VERSION 5.8 ;
BUSBITCHARS "[]" ;
DIVIDERCHAR "/" ;
UNITS
    DATABASE MICRONS 1000 ;
END UNITS

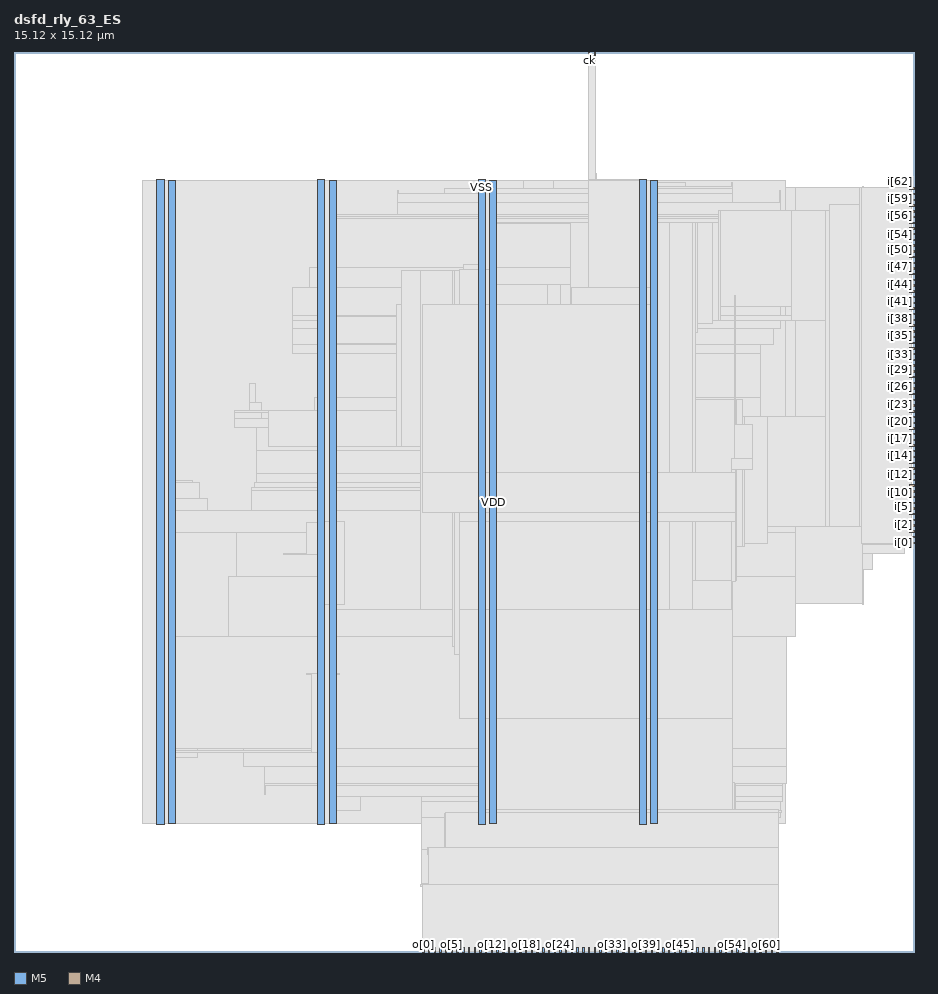
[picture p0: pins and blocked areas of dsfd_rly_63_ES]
MACRO dsfd_rly_63_ES
  FOREIGN dsfd_rly_63_ES 0 0 ;
  CLASS BLOCK ;
  SIZE 15.12 BY 15.12 ;
  PIN ck
    DIRECTION INPUT ;
    USE SIGNAL ;
    PORT
      LAYER M5 ;
        RECT  9.648 15.036 9.672 15.12 ;
    END
  END ck
  PIN i[0]
    DIRECTION INPUT ;
    USE SIGNAL ;
    PORT
      LAYER M4 ;
        RECT  15.036 6.864 15.12 6.888 ;
    END
  END i[0]
  PIN i[10]
    DIRECTION INPUT ;
    USE SIGNAL ;
    PORT
      LAYER M4 ;
        RECT  15.036 7.824 15.12 7.848 ;
    END
  END i[10]
  PIN i[11]
    DIRECTION INPUT ;
    USE SIGNAL ;
    PORT
      LAYER M4 ;
        RECT  15.036 7.92 15.12 7.944 ;
    END
  END i[11]
  PIN i[12]
    DIRECTION INPUT ;
    USE SIGNAL ;
    PORT
      LAYER M4 ;
        RECT  15.036 8.016 15.12 8.04 ;
    END
  END i[12]
  PIN i[13]
    DIRECTION INPUT ;
    USE SIGNAL ;
    PORT
      LAYER M4 ;
        RECT  15.036 8.112 15.12 8.136 ;
    END
  END i[13]
  PIN i[14]
    DIRECTION INPUT ;
    USE SIGNAL ;
    PORT
      LAYER M4 ;
        RECT  15.036 8.208 15.12 8.232 ;
    END
  END i[14]
  PIN i[15]
    DIRECTION INPUT ;
    USE SIGNAL ;
    PORT
      LAYER M4 ;
        RECT  15.036 8.304 15.12 8.328 ;
    END
  END i[15]
  PIN i[16]
    DIRECTION INPUT ;
    USE SIGNAL ;
    PORT
      LAYER M4 ;
        RECT  15.036 8.4 15.12 8.424 ;
    END
  END i[16]
  PIN i[17]
    DIRECTION INPUT ;
    USE SIGNAL ;
    PORT
      LAYER M4 ;
        RECT  15.036 8.496 15.12 8.52 ;
    END
  END i[17]
  PIN i[18]
    DIRECTION INPUT ;
    USE SIGNAL ;
    PORT
      LAYER M4 ;
        RECT  15.036 8.592 15.12 8.616 ;
    END
  END i[18]
  PIN i[19]
    DIRECTION INPUT ;
    USE SIGNAL ;
    PORT
      LAYER M4 ;
        RECT  15.036 8.688 15.12 8.712 ;
    END
  END i[19]
  PIN i[1]
    DIRECTION INPUT ;
    USE SIGNAL ;
    PORT
      LAYER M4 ;
        RECT  15.036 6.96 15.12 6.984 ;
    END
  END i[1]
  PIN i[20]
    DIRECTION INPUT ;
    USE SIGNAL ;
    PORT
      LAYER M4 ;
        RECT  15.036 8.784 15.12 8.808 ;
    END
  END i[20]
  PIN i[21]
    DIRECTION INPUT ;
    USE SIGNAL ;
    PORT
      LAYER M4 ;
        RECT  15.036 8.88 15.12 8.904 ;
    END
  END i[21]
  PIN i[22]
    DIRECTION INPUT ;
    USE SIGNAL ;
    PORT
      LAYER M4 ;
        RECT  15.036 8.976 15.12 9 ;
    END
  END i[22]
  PIN i[23]
    DIRECTION INPUT ;
    USE SIGNAL ;
    PORT
      LAYER M4 ;
        RECT  15.036 9.072 15.12 9.096 ;
    END
  END i[23]
  PIN i[24]
    DIRECTION INPUT ;
    USE SIGNAL ;
    PORT
      LAYER M4 ;
        RECT  15.036 9.168 15.12 9.192 ;
    END
  END i[24]
  PIN i[25]
    DIRECTION INPUT ;
    USE SIGNAL ;
    PORT
      LAYER M4 ;
        RECT  15.036 9.264 15.12 9.288 ;
    END
  END i[25]
  PIN i[26]
    DIRECTION INPUT ;
    USE SIGNAL ;
    PORT
      LAYER M4 ;
        RECT  15.036 9.36 15.12 9.384 ;
    END
  END i[26]
  PIN i[27]
    DIRECTION INPUT ;
    USE SIGNAL ;
    PORT
      LAYER M4 ;
        RECT  15.036 9.456 15.12 9.48 ;
    END
  END i[27]
  PIN i[28]
    DIRECTION INPUT ;
    USE SIGNAL ;
    PORT
      LAYER M4 ;
        RECT  15.036 9.552 15.12 9.576 ;
    END
  END i[28]
  PIN i[29]
    DIRECTION INPUT ;
    USE SIGNAL ;
    PORT
      LAYER M4 ;
        RECT  15.036 9.648 15.12 9.672 ;
    END
  END i[29]
  PIN i[2]
    DIRECTION INPUT ;
    USE SIGNAL ;
    PORT
      LAYER M4 ;
        RECT  15.036 7.056 15.12 7.08 ;
    END
  END i[2]
  PIN i[30]
    DIRECTION INPUT ;
    USE SIGNAL ;
    PORT
      LAYER M4 ;
        RECT  15.036 9.744 15.12 9.768 ;
    END
  END i[30]
  PIN i[31]
    DIRECTION INPUT ;
    USE SIGNAL ;
    PORT
      LAYER M4 ;
        RECT  15.036 9.84 15.12 9.864 ;
    END
  END i[31]
  PIN i[32]
    DIRECTION INPUT ;
    USE SIGNAL ;
    PORT
      LAYER M4 ;
        RECT  15.036 9.936 15.12 9.96 ;
    END
  END i[32]
  PIN i[33]
    DIRECTION INPUT ;
    USE SIGNAL ;
    PORT
      LAYER M4 ;
        RECT  15.036 10.032 15.12 10.056 ;
    END
  END i[33]
  PIN i[34]
    DIRECTION INPUT ;
    USE SIGNAL ;
    PORT
      LAYER M4 ;
        RECT  15.036 10.128 15.12 10.152 ;
    END
  END i[34]
  PIN i[35]
    DIRECTION INPUT ;
    USE SIGNAL ;
    PORT
      LAYER M4 ;
        RECT  15.036 10.224 15.12 10.248 ;
    END
  END i[35]
  PIN i[36]
    DIRECTION INPUT ;
    USE SIGNAL ;
    PORT
      LAYER M4 ;
        RECT  15.036 10.32 15.12 10.344 ;
    END
  END i[36]
  PIN i[37]
    DIRECTION INPUT ;
    USE SIGNAL ;
    PORT
      LAYER M4 ;
        RECT  15.036 10.416 15.12 10.44 ;
    END
  END i[37]
  PIN i[38]
    DIRECTION INPUT ;
    USE SIGNAL ;
    PORT
      LAYER M4 ;
        RECT  15.036 10.512 15.12 10.536 ;
    END
  END i[38]
  PIN i[39]
    DIRECTION INPUT ;
    USE SIGNAL ;
    PORT
      LAYER M4 ;
        RECT  15.036 10.608 15.12 10.632 ;
    END
  END i[39]
  PIN i[3]
    DIRECTION INPUT ;
    USE SIGNAL ;
    PORT
      LAYER M4 ;
        RECT  15.036 7.152 15.12 7.176 ;
    END
  END i[3]
  PIN i[40]
    DIRECTION INPUT ;
    USE SIGNAL ;
    PORT
      LAYER M4 ;
        RECT  15.036 10.704 15.12 10.728 ;
    END
  END i[40]
  PIN i[41]
    DIRECTION INPUT ;
    USE SIGNAL ;
    PORT
      LAYER M4 ;
        RECT  15.036 10.8 15.12 10.824 ;
    END
  END i[41]
  PIN i[42]
    DIRECTION INPUT ;
    USE SIGNAL ;
    PORT
      LAYER M4 ;
        RECT  15.036 10.896 15.12 10.92 ;
    END
  END i[42]
  PIN i[43]
    DIRECTION INPUT ;
    USE SIGNAL ;
    PORT
      LAYER M4 ;
        RECT  15.036 10.992 15.12 11.016 ;
    END
  END i[43]
  PIN i[44]
    DIRECTION INPUT ;
    USE SIGNAL ;
    PORT
      LAYER M4 ;
        RECT  15.036 11.088 15.12 11.112 ;
    END
  END i[44]
  PIN i[45]
    DIRECTION INPUT ;
    USE SIGNAL ;
    PORT
      LAYER M4 ;
        RECT  15.036 11.184 15.12 11.208 ;
    END
  END i[45]
  PIN i[46]
    DIRECTION INPUT ;
    USE SIGNAL ;
    PORT
      LAYER M4 ;
        RECT  15.036 11.28 15.12 11.304 ;
    END
  END i[46]
  PIN i[47]
    DIRECTION INPUT ;
    USE SIGNAL ;
    PORT
      LAYER M4 ;
        RECT  15.036 11.376 15.12 11.4 ;
    END
  END i[47]
  PIN i[48]
    DIRECTION INPUT ;
    USE SIGNAL ;
    PORT
      LAYER M4 ;
        RECT  15.036 11.472 15.12 11.496 ;
    END
  END i[48]
  PIN i[49]
    DIRECTION INPUT ;
    USE SIGNAL ;
    PORT
      LAYER M4 ;
        RECT  15.036 11.568 15.12 11.592 ;
    END
  END i[49]
  PIN i[4]
    DIRECTION INPUT ;
    USE SIGNAL ;
    PORT
      LAYER M4 ;
        RECT  15.036 7.248 15.12 7.272 ;
    END
  END i[4]
  PIN i[50]
    DIRECTION INPUT ;
    USE SIGNAL ;
    PORT
      LAYER M4 ;
        RECT  15.036 11.664 15.12 11.688 ;
    END
  END i[50]
  PIN i[51]
    DIRECTION INPUT ;
    USE SIGNAL ;
    PORT
      LAYER M4 ;
        RECT  15.036 11.76 15.12 11.784 ;
    END
  END i[51]
  PIN i[52]
    DIRECTION INPUT ;
    USE SIGNAL ;
    PORT
      LAYER M4 ;
        RECT  15.036 11.856 15.12 11.88 ;
    END
  END i[52]
  PIN i[53]
    DIRECTION INPUT ;
    USE SIGNAL ;
    PORT
      LAYER M4 ;
        RECT  15.036 11.952 15.12 11.976 ;
    END
  END i[53]
  PIN i[54]
    DIRECTION INPUT ;
    USE SIGNAL ;
    PORT
      LAYER M4 ;
        RECT  15.036 12.048 15.12 12.072 ;
    END
  END i[54]
  PIN i[55]
    DIRECTION INPUT ;
    USE SIGNAL ;
    PORT
      LAYER M4 ;
        RECT  15.036 12.144 15.12 12.168 ;
    END
  END i[55]
  PIN i[56]
    DIRECTION INPUT ;
    USE SIGNAL ;
    PORT
      LAYER M4 ;
        RECT  15.036 12.24 15.12 12.264 ;
    END
  END i[56]
  PIN i[57]
    DIRECTION INPUT ;
    USE SIGNAL ;
    PORT
      LAYER M4 ;
        RECT  15.036 12.336 15.12 12.36 ;
    END
  END i[57]
  PIN i[58]
    DIRECTION INPUT ;
    USE SIGNAL ;
    PORT
      LAYER M4 ;
        RECT  15.036 12.432 15.12 12.456 ;
    END
  END i[58]
  PIN i[59]
    DIRECTION INPUT ;
    USE SIGNAL ;
    PORT
      LAYER M4 ;
        RECT  15.036 12.528 15.12 12.552 ;
    END
  END i[59]
  PIN i[5]
    DIRECTION INPUT ;
    USE SIGNAL ;
    PORT
      LAYER M4 ;
        RECT  15.036 7.344 15.12 7.368 ;
    END
  END i[5]
  PIN i[60]
    DIRECTION INPUT ;
    USE SIGNAL ;
    PORT
      LAYER M4 ;
        RECT  15.036 12.624 15.12 12.648 ;
    END
  END i[60]
  PIN i[61]
    DIRECTION INPUT ;
    USE SIGNAL ;
    PORT
      LAYER M4 ;
        RECT  15.036 12.72 15.12 12.744 ;
    END
  END i[61]
  PIN i[62]
    DIRECTION INPUT ;
    USE SIGNAL ;
    PORT
      LAYER M4 ;
        RECT  15.036 12.816 15.12 12.84 ;
    END
  END i[62]
  PIN i[6]
    DIRECTION INPUT ;
    USE SIGNAL ;
    PORT
      LAYER M4 ;
        RECT  15.036 7.44 15.12 7.464 ;
    END
  END i[6]
  PIN i[7]
    DIRECTION INPUT ;
    USE SIGNAL ;
    PORT
      LAYER M4 ;
        RECT  15.036 7.536 15.12 7.56 ;
    END
  END i[7]
  PIN i[8]
    DIRECTION INPUT ;
    USE SIGNAL ;
    PORT
      LAYER M4 ;
        RECT  15.036 7.632 15.12 7.656 ;
    END
  END i[8]
  PIN i[9]
    DIRECTION INPUT ;
    USE SIGNAL ;
    PORT
      LAYER M4 ;
        RECT  15.036 7.728 15.12 7.752 ;
    END
  END i[9]
  PIN o[0]
    DIRECTION OUTPUT ;
    USE SIGNAL ;
    PORT
      LAYER M5 ;
        RECT  6.864 0 6.888 0.084 ;
    END
  END o[0]
  PIN o[10]
    DIRECTION OUTPUT ;
    USE SIGNAL ;
    PORT
      LAYER M5 ;
        RECT  7.824 0 7.848 0.084 ;
    END
  END o[10]
  PIN o[11]
    DIRECTION OUTPUT ;
    USE SIGNAL ;
    PORT
      LAYER M5 ;
        RECT  7.92 0 7.944 0.084 ;
    END
  END o[11]
  PIN o[12]
    DIRECTION OUTPUT ;
    USE SIGNAL ;
    PORT
      LAYER M5 ;
        RECT  8.016 0 8.04 0.084 ;
    END
  END o[12]
  PIN o[13]
    DIRECTION OUTPUT ;
    USE SIGNAL ;
    PORT
      LAYER M5 ;
        RECT  8.112 0 8.136 0.084 ;
    END
  END o[13]
  PIN o[14]
    DIRECTION OUTPUT ;
    USE SIGNAL ;
    PORT
      LAYER M5 ;
        RECT  8.208 0 8.232 0.084 ;
    END
  END o[14]
  PIN o[15]
    DIRECTION OUTPUT ;
    USE SIGNAL ;
    PORT
      LAYER M5 ;
        RECT  8.304 0 8.328 0.084 ;
    END
  END o[15]
  PIN o[16]
    DIRECTION OUTPUT ;
    USE SIGNAL ;
    PORT
      LAYER M5 ;
        RECT  8.4 0 8.424 0.084 ;
    END
  END o[16]
  PIN o[17]
    DIRECTION OUTPUT ;
    USE SIGNAL ;
    PORT
      LAYER M5 ;
        RECT  8.496 0 8.52 0.084 ;
    END
  END o[17]
  PIN o[18]
    DIRECTION OUTPUT ;
    USE SIGNAL ;
    PORT
      LAYER M5 ;
        RECT  8.592 0 8.616 0.084 ;
    END
  END o[18]
  PIN o[19]
    DIRECTION OUTPUT ;
    USE SIGNAL ;
    PORT
      LAYER M5 ;
        RECT  8.688 0 8.712 0.084 ;
    END
  END o[19]
  PIN o[1]
    DIRECTION OUTPUT ;
    USE SIGNAL ;
    PORT
      LAYER M5 ;
        RECT  6.96 0 6.984 0.084 ;
    END
  END o[1]
  PIN o[20]
    DIRECTION OUTPUT ;
    USE SIGNAL ;
    PORT
      LAYER M5 ;
        RECT  8.784 0 8.808 0.084 ;
    END
  END o[20]
  PIN o[21]
    DIRECTION OUTPUT ;
    USE SIGNAL ;
    PORT
      LAYER M5 ;
        RECT  8.88 0 8.904 0.084 ;
    END
  END o[21]
  PIN o[22]
    DIRECTION OUTPUT ;
    USE SIGNAL ;
    PORT
      LAYER M5 ;
        RECT  8.976 0 9 0.084 ;
    END
  END o[22]
  PIN o[23]
    DIRECTION OUTPUT ;
    USE SIGNAL ;
    PORT
      LAYER M5 ;
        RECT  9.072 0 9.096 0.084 ;
    END
  END o[23]
  PIN o[24]
    DIRECTION OUTPUT ;
    USE SIGNAL ;
    PORT
      LAYER M5 ;
        RECT  9.168 0 9.192 0.084 ;
    END
  END o[24]
  PIN o[25]
    DIRECTION OUTPUT ;
    USE SIGNAL ;
    PORT
      LAYER M5 ;
        RECT  9.264 0 9.288 0.084 ;
    END
  END o[25]
  PIN o[26]
    DIRECTION OUTPUT ;
    USE SIGNAL ;
    PORT
      LAYER M5 ;
        RECT  9.36 0 9.384 0.084 ;
    END
  END o[26]
  PIN o[27]
    DIRECTION OUTPUT ;
    USE SIGNAL ;
    PORT
      LAYER M5 ;
        RECT  9.456 0 9.48 0.084 ;
    END
  END o[27]
  PIN o[28]
    DIRECTION OUTPUT ;
    USE SIGNAL ;
    PORT
      LAYER M5 ;
        RECT  9.552 0 9.576 0.084 ;
    END
  END o[28]
  PIN o[29]
    DIRECTION OUTPUT ;
    USE SIGNAL ;
    PORT
      LAYER M5 ;
        RECT  9.648 0 9.672 0.084 ;
    END
  END o[29]
  PIN o[2]
    DIRECTION OUTPUT ;
    USE SIGNAL ;
    PORT
      LAYER M5 ;
        RECT  7.056 0 7.08 0.084 ;
    END
  END o[2]
  PIN o[30]
    DIRECTION OUTPUT ;
    USE SIGNAL ;
    PORT
      LAYER M5 ;
        RECT  9.744 0 9.768 0.084 ;
    END
  END o[30]
  PIN o[31]
    DIRECTION OUTPUT ;
    USE SIGNAL ;
    PORT
      LAYER M5 ;
        RECT  9.84 0 9.864 0.084 ;
    END
  END o[31]
  PIN o[32]
    DIRECTION OUTPUT ;
    USE SIGNAL ;
    PORT
      LAYER M5 ;
        RECT  9.936 0 9.96 0.084 ;
    END
  END o[32]
  PIN o[33]
    DIRECTION OUTPUT ;
    USE SIGNAL ;
    PORT
      LAYER M5 ;
        RECT  10.032 0 10.056 0.084 ;
    END
  END o[33]
  PIN o[34]
    DIRECTION OUTPUT ;
    USE SIGNAL ;
    PORT
      LAYER M5 ;
        RECT  10.128 0 10.152 0.084 ;
    END
  END o[34]
  PIN o[35]
    DIRECTION OUTPUT ;
    USE SIGNAL ;
    PORT
      LAYER M5 ;
        RECT  10.224 0 10.248 0.084 ;
    END
  END o[35]
  PIN o[36]
    DIRECTION OUTPUT ;
    USE SIGNAL ;
    PORT
      LAYER M5 ;
        RECT  10.32 0 10.344 0.084 ;
    END
  END o[36]
  PIN o[37]
    DIRECTION OUTPUT ;
    USE SIGNAL ;
    PORT
      LAYER M5 ;
        RECT  10.416 0 10.44 0.084 ;
    END
  END o[37]
  PIN o[38]
    DIRECTION OUTPUT ;
    USE SIGNAL ;
    PORT
      LAYER M5 ;
        RECT  10.512 0 10.536 0.084 ;
    END
  END o[38]
  PIN o[39]
    DIRECTION OUTPUT ;
    USE SIGNAL ;
    PORT
      LAYER M5 ;
        RECT  10.608 0 10.632 0.084 ;
    END
  END o[39]
  PIN o[3]
    DIRECTION OUTPUT ;
    USE SIGNAL ;
    PORT
      LAYER M5 ;
        RECT  7.152 0 7.176 0.084 ;
    END
  END o[3]
  PIN o[40]
    DIRECTION OUTPUT ;
    USE SIGNAL ;
    PORT
      LAYER M5 ;
        RECT  10.704 0 10.728 0.084 ;
    END
  END o[40]
  PIN o[41]
    DIRECTION OUTPUT ;
    USE SIGNAL ;
    PORT
      LAYER M5 ;
        RECT  10.8 0 10.824 0.084 ;
    END
  END o[41]
  PIN o[42]
    DIRECTION OUTPUT ;
    USE SIGNAL ;
    PORT
      LAYER M5 ;
        RECT  10.896 0 10.92 0.084 ;
    END
  END o[42]
  PIN o[43]
    DIRECTION OUTPUT ;
    USE SIGNAL ;
    PORT
      LAYER M5 ;
        RECT  10.992 0 11.016 0.084 ;
    END
  END o[43]
  PIN o[44]
    DIRECTION OUTPUT ;
    USE SIGNAL ;
    PORT
      LAYER M5 ;
        RECT  11.088 0 11.112 0.084 ;
    END
  END o[44]
  PIN o[45]
    DIRECTION OUTPUT ;
    USE SIGNAL ;
    PORT
      LAYER M5 ;
        RECT  11.184 0 11.208 0.084 ;
    END
  END o[45]
  PIN o[46]
    DIRECTION OUTPUT ;
    USE SIGNAL ;
    PORT
      LAYER M5 ;
        RECT  11.28 0 11.304 0.084 ;
    END
  END o[46]
  PIN o[47]
    DIRECTION OUTPUT ;
    USE SIGNAL ;
    PORT
      LAYER M5 ;
        RECT  11.376 0 11.4 0.084 ;
    END
  END o[47]
  PIN o[48]
    DIRECTION OUTPUT ;
    USE SIGNAL ;
    PORT
      LAYER M5 ;
        RECT  11.472 0 11.496 0.084 ;
    END
  END o[48]
  PIN o[49]
    DIRECTION OUTPUT ;
    USE SIGNAL ;
    PORT
      LAYER M5 ;
        RECT  11.568 0 11.592 0.084 ;
    END
  END o[49]
  PIN o[4]
    DIRECTION OUTPUT ;
    USE SIGNAL ;
    PORT
      LAYER M5 ;
        RECT  7.248 0 7.272 0.084 ;
    END
  END o[4]
  PIN o[50]
    DIRECTION OUTPUT ;
    USE SIGNAL ;
    PORT
      LAYER M5 ;
        RECT  11.664 0 11.688 0.084 ;
    END
  END o[50]
  PIN o[51]
    DIRECTION OUTPUT ;
    USE SIGNAL ;
    PORT
      LAYER M5 ;
        RECT  11.76 0 11.784 0.084 ;
    END
  END o[51]
  PIN o[52]
    DIRECTION OUTPUT ;
    USE SIGNAL ;
    PORT
      LAYER M5 ;
        RECT  11.856 0 11.88 0.084 ;
    END
  END o[52]
  PIN o[53]
    DIRECTION OUTPUT ;
    USE SIGNAL ;
    PORT
      LAYER M5 ;
        RECT  11.952 0 11.976 0.084 ;
    END
  END o[53]
  PIN o[54]
    DIRECTION OUTPUT ;
    USE SIGNAL ;
    PORT
      LAYER M5 ;
        RECT  12.048 0 12.072 0.084 ;
    END
  END o[54]
  PIN o[55]
    DIRECTION OUTPUT ;
    USE SIGNAL ;
    PORT
      LAYER M5 ;
        RECT  12.144 0 12.168 0.084 ;
    END
  END o[55]
  PIN o[56]
    DIRECTION OUTPUT ;
    USE SIGNAL ;
    PORT
      LAYER M5 ;
        RECT  12.24 0 12.264 0.084 ;
    END
  END o[56]
  PIN o[57]
    DIRECTION OUTPUT ;
    USE SIGNAL ;
    PORT
      LAYER M5 ;
        RECT  12.336 0 12.36 0.084 ;
    END
  END o[57]
  PIN o[58]
    DIRECTION OUTPUT ;
    USE SIGNAL ;
    PORT
      LAYER M5 ;
        RECT  12.432 0 12.456 0.084 ;
    END
  END o[58]
  PIN o[59]
    DIRECTION OUTPUT ;
    USE SIGNAL ;
    PORT
      LAYER M5 ;
        RECT  12.528 0 12.552 0.084 ;
    END
  END o[59]
  PIN o[5]
    DIRECTION OUTPUT ;
    USE SIGNAL ;
    PORT
      LAYER M5 ;
        RECT  7.344 0 7.368 0.084 ;
    END
  END o[5]
  PIN o[60]
    DIRECTION OUTPUT ;
    USE SIGNAL ;
    PORT
      LAYER M5 ;
        RECT  12.624 0 12.648 0.084 ;
    END
  END o[60]
  PIN o[61]
    DIRECTION OUTPUT ;
    USE SIGNAL ;
    PORT
      LAYER M5 ;
        RECT  12.72 0 12.744 0.084 ;
    END
  END o[61]
  PIN o[62]
    DIRECTION OUTPUT ;
    USE SIGNAL ;
    PORT
      LAYER M5 ;
        RECT  12.816 0 12.84 0.084 ;
    END
  END o[62]
  PIN o[6]
    DIRECTION OUTPUT ;
    USE SIGNAL ;
    PORT
      LAYER M5 ;
        RECT  7.44 0 7.464 0.084 ;
    END
  END o[6]
  PIN o[7]
    DIRECTION OUTPUT ;
    USE SIGNAL ;
    PORT
      LAYER M5 ;
        RECT  7.536 0 7.56 0.084 ;
    END
  END o[7]
  PIN o[8]
    DIRECTION OUTPUT ;
    USE SIGNAL ;
    PORT
      LAYER M5 ;
        RECT  7.632 0 7.656 0.084 ;
    END
  END o[8]
  PIN o[9]
    DIRECTION OUTPUT ;
    USE SIGNAL ;
    PORT
      LAYER M5 ;
        RECT  7.728 0 7.752 0.084 ;
    END
  END o[9]
  PIN rs
    DIRECTION INPUT ;
    USE SIGNAL ;
    PORT
      LAYER M5 ;
        RECT  9.744 15.036 9.768 15.12 ;
    END
  END rs
  PIN VDD
    DIRECTION INOUT ;
    USE POWER ;
    PORT
      LAYER M5 ;
        RECT  10.692 2.151 10.812 12.969 ;
        RECT  7.992 2.151 8.112 12.969 ;
        RECT  5.292 2.151 5.412 12.969 ;
        RECT  2.592 2.151 2.712 12.969 ;
    END
  END VDD
  PIN VSS
    DIRECTION INOUT ;
    USE GROUND ;
    PORT
      LAYER M5 ;
        RECT  10.5 2.137 10.62 12.983 ;
        RECT  7.8 2.137 7.92 12.983 ;
        RECT  5.1 2.137 5.22 12.983 ;
        RECT  2.4 2.137 2.52 12.983 ;
    END
  END VSS
  OBS
    LAYER RVTN ;
     RECT  2.16 2.16 12.96 2.295 ;
     RECT  2.16 2.565 12.96 2.835 ;
     RECT  2.16 3.105 12.96 3.375 ;
     RECT  2.16 3.645 12.96 3.915 ;
     RECT  2.16 4.185 12.96 4.455 ;
     RECT  2.16 4.725 12.96 4.995 ;
     RECT  2.16 5.265 12.96 5.535 ;
     RECT  2.16 5.805 12.96 6.075 ;
     RECT  2.16 6.345 12.96 6.615 ;
     RECT  2.16 6.885 12.96 7.155 ;
     RECT  2.16 7.425 12.96 7.695 ;
     RECT  2.16 7.965 12.96 8.235 ;
     RECT  2.16 8.505 12.96 8.775 ;
     RECT  2.16 9.045 12.96 9.315 ;
     RECT  2.16 9.585 12.96 9.855 ;
     RECT  2.16 10.125 12.96 10.395 ;
     RECT  2.16 10.665 12.96 10.935 ;
     RECT  2.16 11.205 12.96 11.475 ;
     RECT  2.16 11.745 12.96 12.015 ;
     RECT  2.16 12.285 12.96 12.555 ;
     RECT  2.16 12.825 12.96 12.96 ;
    LAYER RVTP ;
     RECT  2.16 2.295 12.96 2.565 ;
     RECT  2.16 2.835 12.96 3.105 ;
     RECT  2.16 3.375 12.96 3.645 ;
     RECT  2.16 3.915 12.96 4.185 ;
     RECT  2.16 4.455 12.96 4.725 ;
     RECT  2.16 4.995 12.96 5.265 ;
     RECT  2.16 5.535 12.96 5.805 ;
     RECT  2.16 6.075 12.96 6.345 ;
     RECT  2.16 6.615 12.96 6.885 ;
     RECT  2.16 7.155 12.96 7.425 ;
     RECT  2.16 7.695 12.96 7.965 ;
     RECT  2.16 8.235 12.96 8.505 ;
     RECT  2.16 8.775 12.96 9.045 ;
     RECT  2.16 9.315 12.96 9.585 ;
     RECT  2.16 9.855 12.96 10.125 ;
     RECT  2.16 10.395 12.96 10.665 ;
     RECT  2.16 10.935 12.96 11.205 ;
     RECT  2.16 11.475 12.96 11.745 ;
     RECT  2.16 12.015 12.96 12.285 ;
     RECT  2.16 12.555 12.96 12.825 ;
    LAYER M1 ;
     RECT  2.16 2.151 12.96 12.969 ;
    LAYER M2 ;
     RECT  2.16 2.151 8.563 12.969 ;
     RECT  8.563 2.106 9.059 12.969 ;
     RECT  9.059 2.151 12.96 12.969 ;
     RECT  12.96 2.844 12.983 2.862 ;
     RECT  12.96 5.31 13.127 12.852 ;
     RECT  13.127 5.85 14.279 12.852 ;
     RECT  14.279 6.426 14.315 12.546 ;
     RECT  14.315 6.426 14.351 8.874 ;
     RECT  14.315 9.63 14.351 12.348 ;
     RECT  14.351 9.63 14.387 9.918 ;
     RECT  14.351 6.426 14.423 8.838 ;
     RECT  14.423 6.696 14.459 8.838 ;
     RECT  14.459 6.696 14.963 6.876 ;
     RECT  14.387 9.864 14.963 9.918 ;
     RECT  14.459 8.046 14.999 8.064 ;
     RECT  14.963 9.864 14.999 9.882 ;
     RECT  14.351 10.98 14.999 12.348 ;
     RECT  14.963 6.858 15.035 6.876 ;
     RECT  14.459 8.82 15.035 8.838 ;
     RECT  14.999 10.98 15.035 10.998 ;
     RECT  14.999 12.33 15.035 12.348 ;
    LAYER M3 ;
     RECT  8.82 0.091 8.838 0.139 ;
     RECT  12.168 0.091 12.654 0.187 ;
     RECT  7.668 0.091 7.686 0.523 ;
     RECT  7.128 0.523 7.686 1.099 ;
     RECT  6.84 1.099 7.686 1.147 ;
     RECT  8.82 0.139 8.91 1.147 ;
     RECT  12.132 0.187 12.654 1.675 ;
     RECT  6.84 1.147 8.91 1.723 ;
     RECT  10.656 0.091 11.106 1.723 ;
     RECT  12.06 1.675 12.654 1.723 ;
     RECT  6.84 1.723 12.654 2.263 ;
     RECT  5.115 2.143 5.205 2.371 ;
     RECT  2.415 2.143 2.505 2.413 ;
     RECT  6.84 2.263 12.87 2.533 ;
     RECT  5.115 2.371 5.814 2.605 ;
     RECT  6.84 2.533 12.906 2.605 ;
     RECT  4.212 2.641 4.23 2.803 ;
     RECT  5.115 2.605 12.906 2.803 ;
     RECT  4.212 2.803 12.906 2.839 ;
     RECT  4.212 2.839 12.978 3.109 ;
     RECT  2.415 2.413 2.697 3.271 ;
     RECT  2.415 3.271 3.078 3.415 ;
     RECT  3.852 3.109 12.978 3.415 ;
     RECT  2.415 3.415 12.978 5.297 ;
     RECT  3.6 5.297 12.978 5.305 ;
     RECT  3.6 5.305 13.122 6.305 ;
     RECT  14.256 5.845 14.274 6.421 ;
     RECT  14.256 6.421 14.418 6.691 ;
     RECT  14.256 6.691 14.958 6.853 ;
     RECT  2.415 5.297 2.697 7.051 ;
     RECT  3.744 6.305 13.122 7.051 ;
     RECT  2.415 7.051 13.122 7.421 ;
     RECT  2.415 7.421 3.258 7.619 ;
     RECT  3.996 7.421 13.122 7.757 ;
     RECT  3.996 7.757 12.762 7.799 ;
     RECT  2.415 7.619 3.114 7.889 ;
     RECT  4.032 7.799 12.762 7.889 ;
     RECT  2.415 7.889 3.006 7.925 ;
     RECT  4.068 7.889 12.762 8.033 ;
     RECT  14.256 6.853 15.03 8.239 ;
     RECT  4.068 8.033 12.618 8.429 ;
     RECT  4.068 8.429 12.582 8.815 ;
     RECT  14.184 8.239 15.03 8.843 ;
     RECT  3.708 8.815 12.582 8.969 ;
     RECT  3.708 8.969 4.158 9.101 ;
     RECT  3.96 9.101 4.158 9.239 ;
     RECT  5.04 8.969 12.546 9.311 ;
     RECT  14.184 8.843 14.994 9.355 ;
     RECT  3.96 9.239 4.05 9.545 ;
     RECT  13.68 9.355 14.994 9.835 ;
     RECT  13.644 9.835 14.994 9.931 ;
     RECT  5.115 9.311 12.546 10.057 ;
     RECT  4.68 10.057 12.546 10.201 ;
     RECT  4.68 10.201 12.762 10.471 ;
     RECT  4.68 10.471 12.87 10.603 ;
     RECT  13.644 9.931 15.03 10.603 ;
     RECT  4.68 10.603 15.03 10.697 ;
     RECT  4.68 10.697 12.87 11.165 ;
     RECT  4.968 11.165 12.87 11.507 ;
     RECT  13.644 10.697 15.03 11.515 ;
     RECT  5.115 11.507 12.87 12.331 ;
     RECT  13.608 11.515 15.03 12.331 ;
     RECT  5.115 12.331 15.03 12.353 ;
     RECT  5.115 12.353 14.994 12.389 ;
     RECT  13.716 12.389 14.994 12.557 ;
     RECT  6.444 12.389 12.87 12.587 ;
     RECT  14.22 12.557 14.994 12.653 ;
     RECT  2.415 7.925 2.697 12.707 ;
     RECT  5.115 12.389 5.397 12.707 ;
     RECT  6.444 12.587 12.078 12.749 ;
     RECT  14.22 12.653 14.31 12.749 ;
     RECT  6.444 12.749 6.462 12.785 ;
     RECT  12.852 12.587 12.87 12.785 ;
     RECT  7.236 12.749 12.078 12.821 ;
     RECT  14.22 12.749 14.274 12.845 ;
     RECT  9.648 12.821 12.078 12.857 ;
     RECT  14.256 12.845 14.274 12.857 ;
     RECT  9.648 12.857 9.774 12.893 ;
     RECT  10.515 12.857 11.286 12.929 ;
     RECT  12.06 12.857 12.078 12.929 ;
     RECT  2.415 12.707 2.505 12.977 ;
     RECT  5.115 12.707 5.205 12.977 ;
     RECT  7.815 12.821 7.905 12.977 ;
     RECT  10.515 12.929 10.605 12.977 ;
     RECT  9.756 12.893 9.774 13.085 ;
    LAYER M4 ;
     RECT  2.408 2.148 2.512 12.972 ;
     RECT  2.512 2.418 2.704 12.702 ;
     RECT  3.697 9.072 4.273 9.096 ;
     RECT  4.525 6.672 4.921 6.696 ;
     RECT  2.704 3.36 4.993 3.384 ;
     RECT  4.921 4.656 4.993 4.68 ;
     RECT  4.993 3.36 5.108 4.68 ;
     RECT  4.921 6.672 5.108 7.224 ;
     RECT  4.273 8.496 5.108 9.096 ;
     RECT  5.108 2.148 5.212 12.972 ;
     RECT  5.212 2.418 5.404 12.702 ;
     RECT  5.404 4.656 5.465 4.68 ;
     RECT  5.404 8.496 6.433 9.096 ;
     RECT  5.404 10.224 6.433 10.68 ;
     RECT  6.433 8.496 6.505 10.872 ;
     RECT  5.404 5.76 6.829 7.416 ;
     RECT  6.505 8.496 6.829 11.448 ;
     RECT  6.829 1.104 6.913 1.128 ;
     RECT  6.949 1.632 7.091 1.752 ;
     RECT  7.1 0.528 7.187 0.552 ;
     RECT  7.091 1.68 7.225 1.752 ;
     RECT  6.829 5.76 7.369 11.448 ;
     RECT  7.369 5.136 7.405 11.448 ;
     RECT  7.405 4.992 7.549 11.448 ;
     RECT  7.225 1.68 7.808 2.328 ;
     RECT  7.477 3.936 7.808 3.96 ;
     RECT  7.549 4.992 7.808 11.544 ;
     RECT  7.808 1.68 7.912 12.972 ;
     RECT  7.912 1.68 8.104 12.702 ;
     RECT  8.104 1.68 8.189 2.856 ;
     RECT  8.189 1.152 8.273 2.856 ;
     RECT  7.429 0.096 8.849 0.168 ;
     RECT  8.849 0.144 8.921 0.168 ;
     RECT  8.104 5.328 8.957 11.208 ;
     RECT  8.104 3.936 9.097 4.296 ;
     RECT  8.273 1.728 9.157 2.856 ;
     RECT  8.957 5.424 9.173 11.208 ;
     RECT  9.173 5.52 9.349 11.208 ;
     RECT  8.104 12.24 9.349 12.264 ;
     RECT  9.349 5.52 9.701 12.264 ;
     RECT  9.701 5.52 9.785 13.08 ;
     RECT  9.097 3.888 10.249 4.296 ;
     RECT  9.785 5.52 10.249 12.972 ;
     RECT  10.213 0.096 10.309 0.12 ;
     RECT  9.157 1.728 10.309 2.904 ;
     RECT  10.249 3.888 10.309 12.972 ;
     RECT  10.309 1.728 10.612 12.972 ;
     RECT  10.612 1.728 10.804 12.702 ;
     RECT  10.804 5.568 11.009 12.264 ;
     RECT  10.804 3.408 11.333 4.296 ;
     RECT  11.009 5.712 11.405 12.264 ;
     RECT  11.405 6.24 11.441 12.264 ;
     RECT  11.441 10.416 11.477 12.264 ;
     RECT  11.333 3.408 11.729 3.432 ;
     RECT  11.477 10.56 11.729 12.264 ;
     RECT  11.729 10.608 11.833 12.264 ;
     RECT  11.833 10.608 11.873 12.456 ;
     RECT  10.804 1.728 11.941 2.328 ;
     RECT  10.309 0.096 12.037 0.168 ;
     RECT  11.941 1.728 12.049 2.856 ;
     RECT  12.049 1.68 12.097 2.856 ;
     RECT  12.097 1.68 12.125 2.808 ;
     RECT  11.441 6.24 12.131 9.288 ;
     RECT  12.037 0.096 12.161 0.216 ;
     RECT  12.125 1.68 12.188 2.376 ;
     RECT  12.131 6.816 12.233 9.288 ;
     RECT  12.233 6.816 12.269 9 ;
     RECT  12.188 1.104 12.275 2.376 ;
     RECT  12.275 1.152 12.377 2.376 ;
     RECT  12.377 1.344 12.629 2.376 ;
     RECT  12.161 0.096 12.665 0.12 ;
     RECT  12.269 6.864 12.665 9 ;
     RECT  12.629 2.304 12.773 2.376 ;
     RECT  12.773 2.352 12.889 2.376 ;
     RECT  11.873 10.848 13.057 12.456 ;
     RECT  12.665 7.152 13.633 9 ;
     RECT  13.057 10.608 13.633 12.456 ;
     RECT  13.633 7.152 13.705 12.456 ;
     RECT  13.705 7.152 14.209 12.552 ;
     RECT  14.209 7.152 14.245 12.84 ;
     RECT  14.245 6.864 15.084 12.84 ;
    LAYER M5 ;
     RECT  6.864 0.016 12.84 1.139 ;
     RECT  6.96 1.139 12.84 1.763 ;
     RECT  2.4 2.137 2.52 2.151 ;
     RECT  5.1 2.137 5.22 2.151 ;
     RECT  7.248 1.763 12.84 2.339 ;
     RECT  7.8 2.339 12.84 2.387 ;
     RECT  7.8 2.387 12.072 3.925 ;
     RECT  7.488 3.925 12.072 5.747 ;
     RECT  5.1 2.151 5.412 5.845 ;
     RECT  12.048 5.747 12.072 6.229 ;
     RECT  5.1 5.845 5.544 7.235 ;
     RECT  7.488 5.747 10.812 7.237 ;
     RECT  12.048 6.229 12.12 7.237 ;
     RECT  7.488 7.237 12.12 7.381 ;
     RECT  6.864 7.381 12.12 8.051 ;
     RECT  12.048 8.051 12.12 8.101 ;
     RECT  12.048 8.101 12.408 8.291 ;
     RECT  12.096 8.291 12.408 8.867 ;
     RECT  6.864 8.051 10.812 10.883 ;
     RECT  12.096 8.867 12.12 11.027 ;
     RECT  9.36 10.883 10.812 11.171 ;
     RECT  7.488 10.883 8.112 11.459 ;
     RECT  2.4 2.151 2.712 12.969 ;
     RECT  5.1 7.235 5.412 12.969 ;
     RECT  7.8 11.459 8.112 12.969 ;
     RECT  9.648 11.171 10.812 12.969 ;
     RECT  2.4 12.969 2.52 12.983 ;
     RECT  5.1 12.969 5.22 12.983 ;
     RECT  7.8 12.969 7.92 12.983 ;
     RECT  9.648 12.969 10.62 12.983 ;
     RECT  9.648 12.983 9.768 15.056 ;
  END
END dsfd_rly_63_ES
END LIBRARY
